! (c) 2009  Infineon Technologies AG, Munich
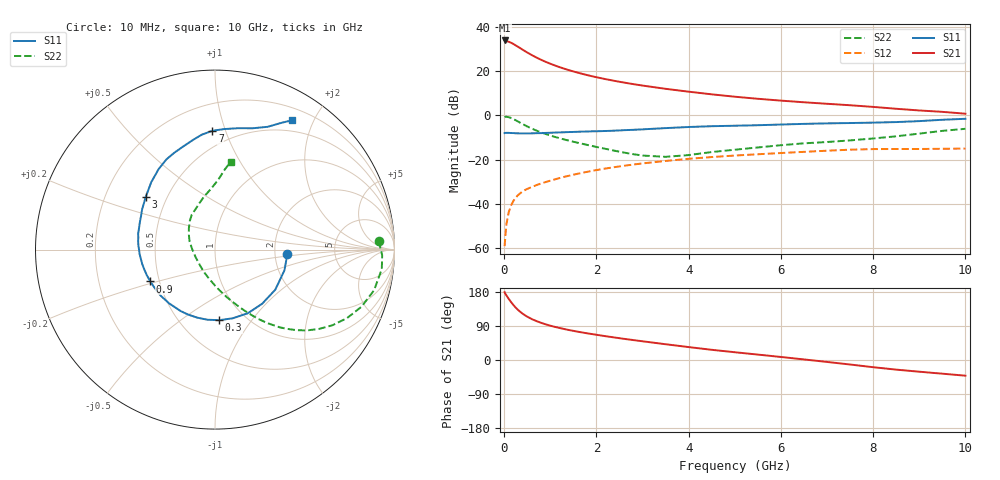
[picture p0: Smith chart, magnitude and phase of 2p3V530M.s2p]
! Infineon Technologies  Discrete & RF Semiconductors
! BFP420
! VCE =  3.5 V,  IC =  30 mA
! Common Emitter S-Parameters:  Nov 2009
# GHz  S  MA  R  50
!  f  S11  S21  S12  S22
! GHz  MAG  ANG  MAG  ANG  MAG  ANG  MAG  ANG
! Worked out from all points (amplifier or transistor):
!   46 points, 10 MHz to 10 GHz, reference 50 ohm
!   highest |S21| = 33.9 dB at 10 MHz (marker M1)
!   |S21| within 3 dB of that: start of sweep to 311.6 MHz
!   unconditionally stable (mu >= 1): start of sweep to 16.01 MHz; 1.577 GHz to end of sweep
!   at 300 MHz: K = 0.41, MSG = 33.6 dB, |S12| = -36.1 dB
!   at 1.7 GHz: K = 1.02, MAG = 21.5 dB, |S12| = -25.9 dB
!   at 10 GHz: K = 1.06, MAG = 6.4 dB, |S12| = -15.0 dB
!   lowest NFmin = 1.51 dB at 900 MHz
!   S11 on the Smith chart (normalised r, x): 10 MHz: 2.32, -0.15; 300 MHz: 0.76, -0.71; 900 MHz: 0.45, -0.19; 3 GHz: 0.38, +0.29; 7 GHz: 0.38, +0.90; 10 GHz: 0.35, +1.71
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0.01  0.3994 -3.9  49.8 178.9  0.0011 80.4  0.9138 2.9
0.02  0.4023 -6.2  48.55 175.8  0.0015 82.8  0.9318 -1.9
0.05  0.4038 -16.6  47.93 170.3  0.0035 78.6  0.9358 -6.7
0.1  0.4034 -33.7  46.54 161.2  0.0065 77.1  0.9144 -14.4
0.15  0.4 -48.9  44.2 152.8  0.0092 73.1  0.876 -21.3
0.2  0.3991 -62.8  41.52 145.2  0.0116 69.5  0.829 -27.4
0.25  0.3952 -75.5  38.58 138.3  0.0138 66.8  0.7792 -32.7
0.3  0.394 -86.5  35.88 132.3  0.0157 64.5  0.7292 -37.3
0.4  0.3918 -104.7  30.83 122.3  0.019 61.4  0.6393 -44.6
0.45  0.3918 -112.4  28.61 118.2  0.0204 60.4  0.5997 -47.5
0.6  0.3938 -130.5  23.21 107.9  0.0241 58.7  0.5034 -54.5
0.7  0.3969 -139.7  20.46 102.7  0.0265 58.3  0.4542 -58.1
0.9  0.4021 -153.8  16.36 94.1  0.0311 58.0  0.3806 -63.9
1.3  0.4164 -172.9  11.46 81.8  0.0407 57.6  0.2864 -74.0
1.7  0.4309 173.6  8.709 72.5  0.0505 56.1  0.2272 -83.9
2.2  0.4451 160.3  6.633 62.8  0.063 53.0  0.1753 -97.5
3  0.4844 142.9  4.748 49.4  0.0821 46.5  0.1237 -130.1
3.5  0.517 133.4  4.007 41.6  0.0934 41.9  0.1157 -157.1
5.5  0.601 107.2  2.383 14.3  0.1324 23.2  0.1886 140.5
7  0.6619 91.3  1.837 -5.1  0.1593 9.1  0.2504 115.6
8.5  0.7081 72.7  1.416 -25.4  0.174 -8.0  0.3374 94.1
10  0.8403 59.1  1.095 -41.4  0.1779 -19.4  0.4987 79.8
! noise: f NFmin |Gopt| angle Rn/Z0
0.9  1.51  0.26  -155  0.13
1.8  1.78  0.33  -142  0.14
2.4  1.96  0.3  -136  0.18
3  1.98  0.38  -127  0.2
4  2.11  0.47  -111  0.31
5  2.57  0.53  -94  0.51
6  3  0.57  -82  0.74
